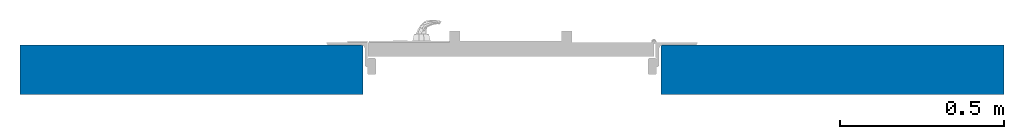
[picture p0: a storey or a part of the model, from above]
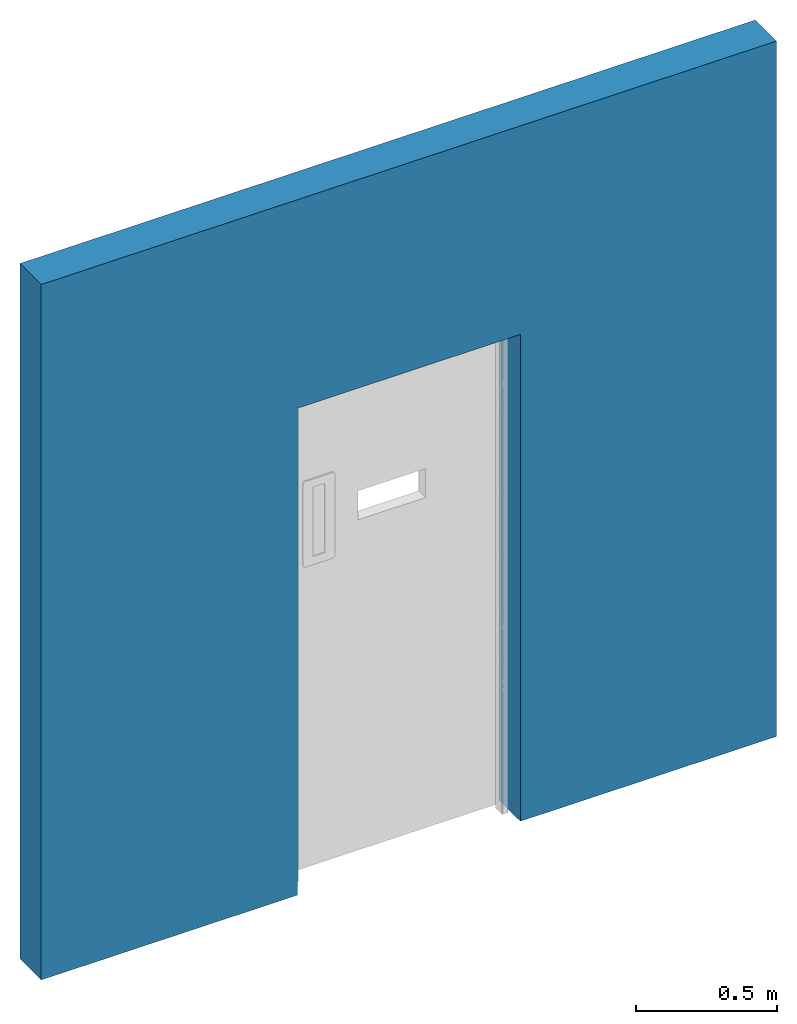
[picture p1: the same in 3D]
Properties of the parts of a building model (IFC2X3)

# File
Description: ViewDefinition [CoordinationView_V2.0]
Time: 2015-03-31T15:19:39
Written by: The EXPRESS Data Manager Version 5.01.0100.02.64mod : 6 Jun 2012
Made in: 20130709_2115(x64) - Exporter 3.12.0.0 - Alternate UI 2.12.0.0
Comment: STEP Physical File produced by: The EXPRESS Data Manager Version 5.01.0100.02.64mod : 6 Jun 2012 * Module: EDMstepFileFactory/EDMstandAlone * Creation date: Tue Mar 31 15:19:39 2015 * Host: NCL-TA29 * Database: C:\Users\Vickersc\AppData\Local\Temp\{F4EE776D-CFA3-4018-9999-130590EFAC93}\ifc * Database version: 5507 * Database creation date: Tue Mar 31 15:19:38 2015 * Schema: IFC2X3 * Model: DataRepository.ifc * Model creation date: Tue Mar 31 15:19:38 2015 * Header model: DataRepository.ifc_HeaderModel * Header model creation date: Tue Mar 31 15:19:38 2015 * EDMuser: sdai-user * EDMgroup: sdai-group * License ID and type: 5605 : Permanent license. Expiry date: * EDMstepFileFactory options: 020000

# IfcProject
LongName: X:\NBL\Manufacturer\A\Assa Abloy 0060A_8204\WIP\Xbim\Batch3\IFC\NBS_AssaAbloyLtd_DrsetSym_LambethPoliceCellDoor_Single.ifc

# IfcSite, Default
RefLatitude: 42, 24, 53, 508911; RefLongitude: -71, -15, -29, -58837; RefElevation: 0 mm

# IfcBuildingStorey, Level 1
LongName: Level 1; Elevation: 0 mm

# IfcDoor: 910x2100mm, NBS_AssaAbloyLtd_DrsetSym_LambethPoliceCellDoor_Single:910x2100mm:1524841
In: Level 1
Type - ParameterTakesPrecedence: no; Sizeable: no; Material: NBS_Concept, NBS_Glass_Single
Type - Pset_DoorCommon - AcousticRating: Unrated; FireExit: no; FireRating: Unrated; GlazingAreaFraction: 0; HandicapAccessible: yes; HasDrive: no; Infiltration: 0 m3/s; IsExternal: no; Reference: n/a; SecurityRating: Unrated; SelfClosing: no; SmokeStop: no; ThermalTransmittance: 0 kg/K/s3
Type - COBie - AccessibilityPerformance: n/a; CodePerformance: n/a; Constituents: n/a; Features: n/a; Finish: n/a; Grade: n/a; Manufacturer: sales@assaabloy.co.uk; Material: n/a; ModelReference: Lambeth Police Cell Door; NominalHeight: 2100 mm; NominalLength: 0 mm; NominalWidth: 910 mm; ReplacementCost: n/a; Shape: Rectangle; Size: 910 x 2100 mm; SustainabilityPerformance: n/a; WarrantyDescription: n/a; WarrantyDurationParts: n/a; WarrantyGuarantorParts: n/a; AssetType: Fixed; Category: n/a; DurationUnit: year; Name: DoorsetSystem_LambethPoliceCellDoor_Single-910x2100mm_AssaAbloyLtd; WarrantyDurationUnit: year; ExpectedLife: n/a; Description: Single metal police cell door; Color: n/a; ModelNumber: n/a; WarrantyDurationLabor: n/a; WarrantyGuarantorLabor: n/a
Type - NBS_General - Revision: n/a; NBSOfficeMasterTag: n/a; Author: NBS; BIMObjectName: NBS_AssaAbloyLtd_DoorsetSystem_LambethPoliceCellDoor_Single-910x2100mm; ManufacturerName: Assa Abloy Ltd; ManufacturerURL: www.assaabloy.co.uk; NBSCertification: www.nationalbimlibrary.com/assa-abloy/single-metal-lambeth-police-cell-door; NBSDescription: Doorset system; NBSNote: 25-90-20/120; NBSReference: 25-50-20/120; NBSTypeID: n/a; Uniclass2: 25-30-20/120; Version: 1; ProductInformation: www.assaabloy.co.uk/en/local/uk/About-ASSA-ABLOY/UK-organisation/Security-Doors/Products1/Powershield-Doors/
Type - NBS_Data - AcousticRatingOptions: n/a; AirTransferGrille: no; AirTransferGrilleSize: n/a; AlternativeDoorsetGlazing: n/a; AntiFingerTrapRequirement: no; AutomaticHardware: n/a; BreakoutFacility: no; CloserOptions: n/a; Configuration: Single leaf, single action; DoorSeal: no; DoorsetFasteners: n/a; DoorsetType: Metal; DoorstopOptions: Floor mounted door stop, Wall mounted door stop; EmergencyPanicOperation: False; FireRatingOptions: n/a; FrameFinish: n/a; FrameFinishlOptions: Epoxy powder primed, Polyester powder coated, Satin polish 180-240 grit (stainless steel only), Patterned finish (stainless steel only), Laminates; FrameMaterial: n/a; FrameMaterialOptions: Steel Galvatite ZF ‘Galvanneal’, Stainless Steel Grade 304, Stainless Steel Grade 349; FrameProfileOptions: n/a; FrameRevealFiller: n/a; FrameSeal: no; FrameWidthOptions: n/a; GlassType: n/a; Hanging: n/a; HardwareSetOptions: n/a; LeafFacingOptions: Epoxy powder primed, Polyester powder coated, Satin polish 180-240 grit (stainless steel only), Patterned finish (stainless steel only), Laminates; LeafMaterialOptions: Steel Galvatite ZF ‘Galvanneal’, Stainless Steel Grade 304, Stainless Steel Grade 316; LeafSwingOptions: n/a; LockingOptions: n/a; MaximumStructuralOpening: Please contact ASSA ABLOY Security Doors for more details; MinimumStructuralOpening: Please contact ASSA ABLOY Security Doors for more details; Operating: n/a; OperationOptions: n/a; OverPanels: n/a; PlatesAndStops: n/a; Securing: n/a; SecurityRatingOptions: n/a; SidePanels: n/a; SignageFireOptions: n/a; SuitableLocation: Police cell; SystemAccessories: n/a; ThresholdBase: n/a; ThresholdRequired: no; ThresholdStripping: no; Trim: n/a; VisionPanelConfiguration: n/a; VisionPanelOptions: n/a
OverallHeight: 2100 mm; OverallWidth: 910 mm
COBie - AssetIdentifier: n/a; BarCode: n/a; InstallationDate: 1900-12-31T23:59:59; SerialNumber: n/a; TagNumber: n/a; WarrantyStartDate: n/a
NBS_Data - ComponentNumber: n/a; DoorNumber: n/a; ElectronicLock: no; FloorFinish: n/a; Handing: n/a; HardwareSet: DT-HW-SG2; HeadDetail: n/a; HoldOpen: no; JambDetail: n/a; KeySuiting: n/a; LeafEdgings: n/a; LeafFacing: n/a; LeafSwing: Outward opening; OpeningMechanism: no; SignageFire: n/a; SignageSecurity: n/a; SignageWayfinding: n/a

# IfcWallStandardCase: Basic Wall:NBS_Int_Concept, Basic Wall:NBS_Int_Concept:2301
In: Level 1
Type - PredefinedType: STANDARD; Material: nbl_Concept 150 mm
